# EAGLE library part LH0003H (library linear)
OP AMP

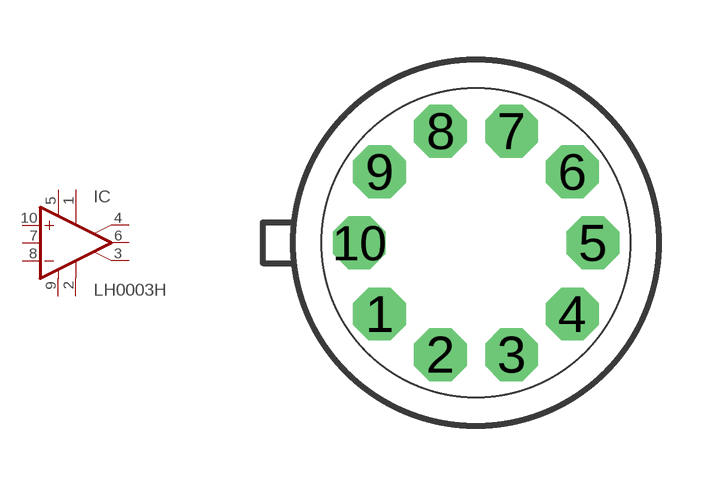
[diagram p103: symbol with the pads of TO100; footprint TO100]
Designator prefix IC

## LH0003H  [TO100]
1  CMP1  pas
2  BS2
3  BS1
4  CMP1/CL  pas
5  V+  pwr
6  OUT  out
7  CMP2  pas
8  -IN  in
9  V-  pwr
10  +IN  in

## Footprint TO100 (pad centres in mm)
Metal Can Package
drill 0.813 octagon: 1 -2.413,-1.778; 2 -0.889,-2.794; 3 0.889,-2.794; 4 2.413,-1.778; 5 2.921,0; 6 2.413,1.778; 7 0.889,2.794; 8 -0.889,2.794; 9 -2.413,1.778; 10 -2.921,0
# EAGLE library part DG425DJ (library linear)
CMOS SWITCH

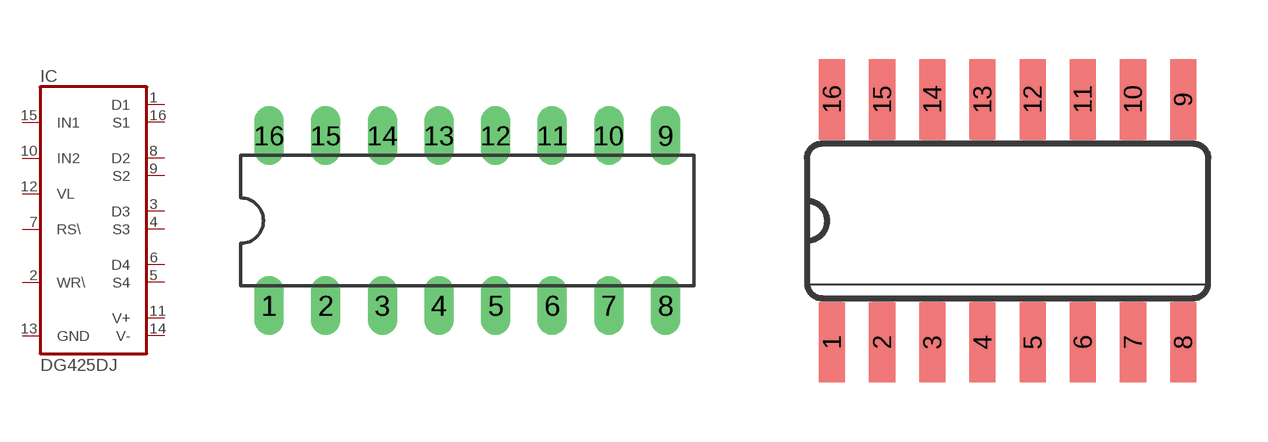
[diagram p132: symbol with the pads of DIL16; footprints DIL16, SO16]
Designator prefix IC

## DG425DJN  [DIL16]
1  D1
2  WR\  in
3  D3
4  S3
5  S4
6  D4
7  RS\  in
8  D2
9  S2
10  IN2  in
11  V+  pwr
12  VL  in
13  GND  pwr
14  V-  pwr
15  IN1  in
16  S1

## DG425DJD  [SO16]
Pads as for DIL16

## Footprint DIL16 (pad centres in mm)
Dual In Line Package
drill 0.813 long: 1 -8.89,-3.81; 2 -6.35,-3.81; 3 -3.81,-3.81; 4 -1.27,-3.81; 5 1.27,-3.81; 6 3.81,-3.81; 7 6.35,-3.81; 8 8.89,-3.81; 9 8.89,3.81; 10 6.35,3.81; 11 3.81,3.81; 12 1.27,3.81; 13 -1.27,3.81; 14 -3.81,3.81; 15 -6.35,3.81; 16 -8.89,3.81

## Footprint SO16 (pad centres in mm)
Small Outline Package 16
smd 0.66 x 2.032: 1 -4.445,-3.073; 2 -3.175,-3.073; 3 -1.905,-3.073; 4 -0.635,-3.073; 5 0.635,-3.073; 6 1.905,-3.073; 7 3.175,-3.073; 8 4.445,-3.073; 9 4.445,3.073; 10 3.175,3.073; 11 1.905,3.073; 12 0.635,3.073; 13 -0.635,3.073; 14 -1.905,3.073; 15 -3.175,3.073; 16 -4.445,3.073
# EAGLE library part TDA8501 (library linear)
PAL/NTSC encoder Philips Semiconductors

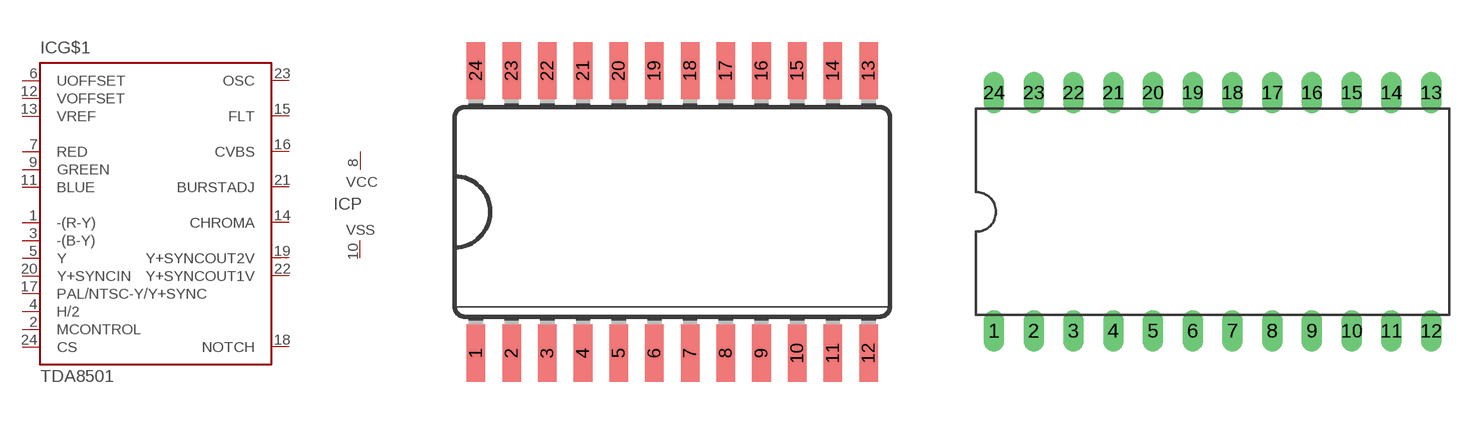
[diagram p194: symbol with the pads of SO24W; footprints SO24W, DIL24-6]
Designator prefix IC; gates G$1=TDA8501 P=VCCVSS

## TDA8501T  [SO24W]
1  G$1:-(R-Y)  in
2  G$1:MCONTROL  in
3  G$1:-(B-Y)  in
4  G$1:H/2  in
5  G$1:Y  in
6  G$1:UOFFSET  pas
7  G$1:RED  in
8  P:VCC  pwr
9  G$1:GREEN  in
10  P:VSS  pwr
11  G$1:BLUE  in
12  G$1:VOFFSET  pas
13  G$1:VREF  pas
14  G$1:CHROMA  out
15  G$1:FLT  pas
16  G$1:CVBS  out
17  G$1:PAL/NTSC-Y/Y+SYNC  pas
18  G$1:NOTCH  pas
19  G$1:Y+SYNCOUT2V  out
20  G$1:Y+SYNCIN  in
21  G$1:BURSTADJ  pas
22  G$1:Y+SYNCOUT1V  out
23  G$1:OSC  pas
24  G$1:CS  in

## TDA8501  [DIL24-6]
Pads as for SO24W

## Footprint SO24W (pad centres in mm)
Small Outline Package 24 wide
smd 0.66 x 2.032: 1 -6.985,-5.029; 2 -5.715,-5.029; 3 -4.445,-5.029; 4 -3.175,-5.029; 5 -1.905,-5.029; 6 -0.635,-5.029; 7 0.635,-5.029; 8 1.905,-5.029; 9 3.175,-5.029; 10 4.445,-5.029; 11 5.715,-5.029; 12 6.985,-5.029; 13 6.985,5.029; 14 5.715,5.029; 15 4.445,5.029; 16 3.175,5.029; 17 1.905,5.029; 18 0.635,5.029; 19 -0.635,5.029; 20 -1.905,5.029; 21 -3.175,5.029; 22 -4.445,5.029; 23 -5.715,5.029; 24 -6.985,5.029

## Footprint DIL24-6 (pad centres in mm)
Dual In Line Package 0.6 inch
drill 0.813 long: 1 -13.97,-7.62; 2 -11.43,-7.62; 3 -8.89,-7.62; 4 -6.35,-7.62; 5 -3.81,-7.62; 6 -1.27,-7.62; 7 1.27,-7.62; 8 3.81,-7.62; 9 6.35,-7.62; 10 8.89,-7.62; 11 11.43,-7.62; 12 13.97,-7.62; 13 13.97,7.62; 14 11.43,7.62; 15 8.89,7.62; 16 6.35,7.62; 17 3.81,7.62; 18 1.27,7.62; 19 -1.27,7.62; 20 -3.81,7.62; 21 -6.35,7.62; 22 -8.89,7.62; 23 -11.43,7.62; 24 -13.97,7.62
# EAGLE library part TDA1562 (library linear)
70 W High Efficiency Power Amplifier with diagnostic facility

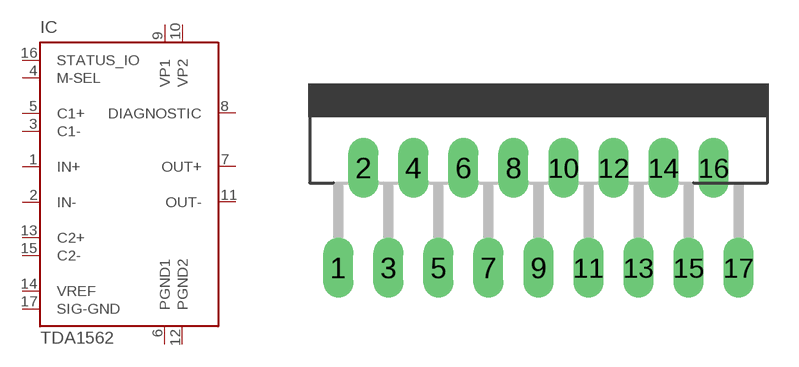
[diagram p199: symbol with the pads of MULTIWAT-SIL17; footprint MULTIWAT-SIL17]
Designator prefix IC

## TDA1562Q  [MULTIWAT-SIL17]
1  IN+  in
2  IN-  in
3  C1-  pas
4  M-SEL  in
5  C1+  pas
6  PGND1  pwr
7  OUT+  out
8  DIAGNOSTIC  out
9  VP1  pwr
10  VP2  pwr
11  OUT-  out
12  PGND2  pwr
13  C2+  pas
14  VREF  in
15  C2-  pas
16  STATUS_IO  in
17  SIG-GND  in

## Footprint MULTIWAT-SIL17 (pad centres in mm)
DBS17P plastic DIL-bent-SIL power package 17 leads (lead length 12 mm) SOT243-1
drill 1.016 long: 1 -10.16,-7.62; 2 -8.89,-2.54; 3 -7.62,-7.62; 4 -6.35,-2.54; 5 -5.08,-7.62; 6 -3.81,-2.54; 7 -2.54,-7.62; 8 -1.27,-2.54; 9 0,-7.62; 10 1.27,-2.54; 11 2.54,-7.62; 12 3.81,-2.54; 13 5.08,-7.62; 14 6.35,-2.54; 15 7.62,-7.62; 16 8.89,-2.54; 17 10.16,-7.62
